VERSION 5.7 ;
  NOWIREEXTENSIONATPIN ON ;
  DIVIDERCHAR "/" ;
  BUSBITCHARS "[]" ;
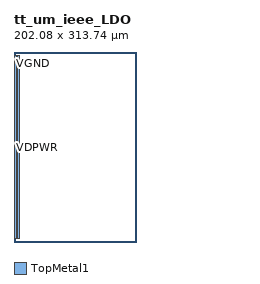
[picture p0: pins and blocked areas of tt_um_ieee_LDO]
MACRO tt_um_ieee_LDO
  CLASS BLOCK ;
  FOREIGN tt_um_ieee_LDO ;
  ORIGIN 0.000 0.000 ;
  SIZE 202.080 BY 313.740 ;
  PIN VDPWR
    DIRECTION INOUT ;
    USE POWER ;
    PORT
      LAYER TopMetal1 ;
        RECT 1.000 5.000 3.400 308.000 ;
    END
  END VDPWR
  PIN VGND
    DIRECTION INOUT ;
    USE GROUND ;
    PORT
      LAYER TopMetal1 ;
        RECT 6.000 5.000 8.400 308.000 ;
    END
  END VGND
END tt_um_ieee_LDO
END LIBRARY

